VERSION 5.7 ;
  NOWIREEXTENSIONATPIN ON ;
  DIVIDERCHAR "/" ;
  BUSBITCHARS "[]" ;
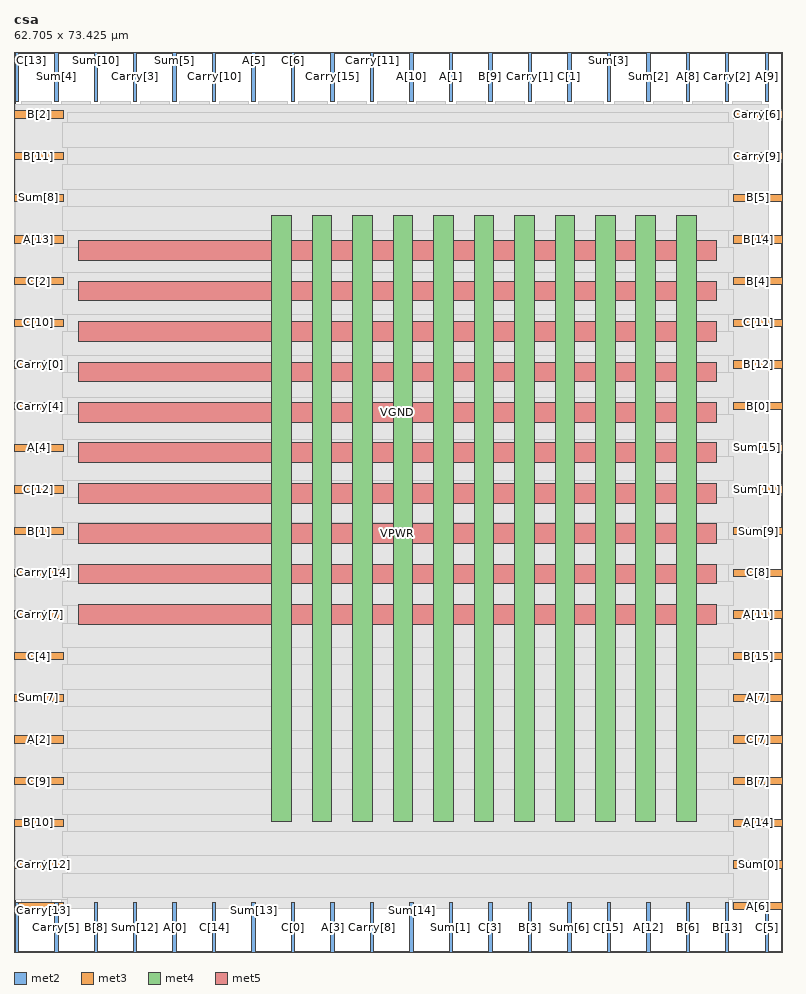
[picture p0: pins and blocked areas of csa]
MACRO csa
  CLASS BLOCK ;
  FOREIGN csa ;
  ORIGIN 0.000 0.000 ;
  SIZE 62.705 BY 73.425 ;
  PIN A[0]
    DIRECTION INPUT ;
    USE SIGNAL ;
    ANTENNAGATEAREA 0.196500 ;
    PORT
      LAYER met2 ;
        RECT 12.970 0.000 13.250 4.000 ;
    END
  END A[0]
  PIN A[10]
    DIRECTION INPUT ;
    USE SIGNAL ;
    ANTENNAGATEAREA 0.196500 ;
    PORT
      LAYER met2 ;
        RECT 32.290 69.425 32.570 73.425 ;
    END
  END A[10]
  PIN A[11]
    DIRECTION INPUT ;
    USE SIGNAL ;
    ANTENNAGATEAREA 0.196500 ;
    PORT
      LAYER met3 ;
        RECT 58.705 27.240 62.705 27.840 ;
    END
  END A[11]
  PIN A[12]
    DIRECTION INPUT ;
    USE SIGNAL ;
    ANTENNAGATEAREA 0.126000 ;
    PORT
      LAYER met2 ;
        RECT 51.610 0.000 51.890 4.000 ;
    END
  END A[12]
  PIN A[13]
    DIRECTION INPUT ;
    USE SIGNAL ;
    ANTENNAGATEAREA 0.196500 ;
    PORT
      LAYER met3 ;
        RECT 0.000 57.840 4.000 58.440 ;
    END
  END A[13]
  PIN A[14]
    DIRECTION INPUT ;
    USE SIGNAL ;
    ANTENNAGATEAREA 0.196500 ;
    PORT
      LAYER met3 ;
        RECT 58.705 10.240 62.705 10.840 ;
    END
  END A[14]
  PIN A[15]
    DIRECTION INPUT ;
    USE SIGNAL ;
    ANTENNAGATEAREA 0.126000 ;
    PORT
      LAYER met3 ;
        RECT 0.000 3.440 4.000 4.040 ;
    END
  END A[15]
  PIN A[1]
    DIRECTION INPUT ;
    USE SIGNAL ;
    ANTENNAGATEAREA 0.196500 ;
    PORT
      LAYER met2 ;
        RECT 35.510 69.425 35.790 73.425 ;
    END
  END A[1]
  PIN A[2]
    DIRECTION INPUT ;
    USE SIGNAL ;
    ANTENNAGATEAREA 0.126000 ;
    PORT
      LAYER met3 ;
        RECT 0.000 17.040 4.000 17.640 ;
    END
  END A[2]
  PIN A[3]
    DIRECTION INPUT ;
    USE SIGNAL ;
    ANTENNAGATEAREA 0.196500 ;
    PORT
      LAYER met2 ;
        RECT 25.850 0.000 26.130 4.000 ;
    END
  END A[3]
  PIN A[4]
    DIRECTION INPUT ;
    USE SIGNAL ;
    ANTENNAGATEAREA 0.196500 ;
    PORT
      LAYER met3 ;
        RECT 0.000 40.840 4.000 41.440 ;
    END
  END A[4]
  PIN A[5]
    DIRECTION INPUT ;
    USE SIGNAL ;
    ANTENNAGATEAREA 0.196500 ;
    PORT
      LAYER met2 ;
        RECT 19.410 69.425 19.690 73.425 ;
    END
  END A[5]
  PIN A[6]
    DIRECTION INPUT ;
    USE SIGNAL ;
    ANTENNAGATEAREA 0.196500 ;
    PORT
      LAYER met3 ;
        RECT 58.705 3.440 62.705 4.040 ;
    END
  END A[6]
  PIN A[7]
    DIRECTION INPUT ;
    USE SIGNAL ;
    ANTENNAGATEAREA 0.196500 ;
    PORT
      LAYER met3 ;
        RECT 58.705 20.440 62.705 21.040 ;
    END
  END A[7]
  PIN A[8]
    DIRECTION INPUT ;
    USE SIGNAL ;
    ANTENNAGATEAREA 0.196500 ;
    PORT
      LAYER met2 ;
        RECT 54.830 69.425 55.110 73.425 ;
    END
  END A[8]
  PIN A[9]
    DIRECTION INPUT ;
    USE SIGNAL ;
    ANTENNAGATEAREA 0.196500 ;
    PORT
      LAYER met2 ;
        RECT 61.270 69.425 61.550 73.425 ;
    END
  END A[9]
  PIN B[0]
    DIRECTION INPUT ;
    USE SIGNAL ;
    ANTENNAGATEAREA 0.126000 ;
    PORT
      LAYER met3 ;
        RECT 58.705 44.240 62.705 44.840 ;
    END
  END B[0]
  PIN B[10]
    DIRECTION INPUT ;
    USE SIGNAL ;
    ANTENNAGATEAREA 0.196500 ;
    PORT
      LAYER met3 ;
        RECT 0.000 10.240 4.000 10.840 ;
    END
  END B[10]
  PIN B[11]
    DIRECTION INPUT ;
    USE SIGNAL ;
    ANTENNAGATEAREA 0.196500 ;
    PORT
      LAYER met3 ;
        RECT 0.000 64.640 4.000 65.240 ;
    END
  END B[11]
  PIN B[12]
    DIRECTION INPUT ;
    USE SIGNAL ;
    ANTENNAGATEAREA 0.126000 ;
    PORT
      LAYER met3 ;
        RECT 58.705 47.640 62.705 48.240 ;
    END
  END B[12]
  PIN B[13]
    DIRECTION INPUT ;
    USE SIGNAL ;
    ANTENNAGATEAREA 0.196500 ;
    PORT
      LAYER met2 ;
        RECT 58.050 0.000 58.330 4.000 ;
    END
  END B[13]
  PIN B[14]
    DIRECTION INPUT ;
    USE SIGNAL ;
    ANTENNAGATEAREA 0.126000 ;
    PORT
      LAYER met3 ;
        RECT 58.705 57.840 62.705 58.440 ;
    END
  END B[14]
  PIN B[15]
    DIRECTION INPUT ;
    USE SIGNAL ;
    ANTENNAGATEAREA 0.196500 ;
    PORT
      LAYER met3 ;
        RECT 58.705 23.840 62.705 24.440 ;
    END
  END B[15]
  PIN B[1]
    DIRECTION INPUT ;
    USE SIGNAL ;
    ANTENNAGATEAREA 0.196500 ;
    PORT
      LAYER met3 ;
        RECT 0.000 34.040 4.000 34.640 ;
    END
  END B[1]
  PIN B[2]
    DIRECTION INPUT ;
    USE SIGNAL ;
    ANTENNAGATEAREA 0.196500 ;
    PORT
      LAYER met3 ;
        RECT 0.000 68.040 4.000 68.640 ;
    END
  END B[2]
  PIN B[3]
    DIRECTION INPUT ;
    USE SIGNAL ;
    ANTENNAGATEAREA 0.196500 ;
    PORT
      LAYER met2 ;
        RECT 41.950 0.000 42.230 4.000 ;
    END
  END B[3]
  PIN B[4]
    DIRECTION INPUT ;
    USE SIGNAL ;
    ANTENNAGATEAREA 0.196500 ;
    PORT
      LAYER met3 ;
        RECT 58.705 54.440 62.705 55.040 ;
    END
  END B[4]
  PIN B[5]
    DIRECTION INPUT ;
    USE SIGNAL ;
    ANTENNAGATEAREA 0.196500 ;
    PORT
      LAYER met3 ;
        RECT 58.705 61.240 62.705 61.840 ;
    END
  END B[5]
  PIN B[6]
    DIRECTION INPUT ;
    USE SIGNAL ;
    ANTENNAGATEAREA 0.196500 ;
    PORT
      LAYER met2 ;
        RECT 54.830 0.000 55.110 4.000 ;
    END
  END B[6]
  PIN B[7]
    DIRECTION INPUT ;
    USE SIGNAL ;
    ANTENNAGATEAREA 0.196500 ;
    PORT
      LAYER met3 ;
        RECT 58.705 13.640 62.705 14.240 ;
    END
  END B[7]
  PIN B[8]
    DIRECTION INPUT ;
    USE SIGNAL ;
    ANTENNAGATEAREA 0.196500 ;
    PORT
      LAYER met2 ;
        RECT 6.530 0.000 6.810 4.000 ;
    END
  END B[8]
  PIN B[9]
    DIRECTION INPUT ;
    USE SIGNAL ;
    ANTENNAGATEAREA 0.196500 ;
    PORT
      LAYER met2 ;
        RECT 38.730 69.425 39.010 73.425 ;
    END
  END B[9]
  PIN C[0]
    DIRECTION INPUT ;
    USE SIGNAL ;
    ANTENNAGATEAREA 0.196500 ;
    PORT
      LAYER met2 ;
        RECT 22.630 0.000 22.910 4.000 ;
    END
  END C[0]
  PIN C[10]
    DIRECTION INPUT ;
    USE SIGNAL ;
    ANTENNAGATEAREA 0.196500 ;
    PORT
      LAYER met3 ;
        RECT 0.000 51.040 4.000 51.640 ;
    END
  END C[10]
  PIN C[11]
    DIRECTION INPUT ;
    USE SIGNAL ;
    ANTENNAGATEAREA 0.196500 ;
    PORT
      LAYER met3 ;
        RECT 58.705 51.040 62.705 51.640 ;
    END
  END C[11]
  PIN C[12]
    DIRECTION INPUT ;
    USE SIGNAL ;
    ANTENNAGATEAREA 0.196500 ;
    PORT
      LAYER met3 ;
        RECT 0.000 37.440 4.000 38.040 ;
    END
  END C[12]
  PIN C[13]
    DIRECTION INPUT ;
    USE SIGNAL ;
    ANTENNAGATEAREA 0.196500 ;
    PORT
      LAYER met2 ;
        RECT 0.090 69.425 0.370 73.425 ;
    END
  END C[13]
  PIN C[14]
    DIRECTION INPUT ;
    USE SIGNAL ;
    ANTENNAGATEAREA 0.196500 ;
    PORT
      LAYER met2 ;
        RECT 16.190 0.000 16.470 4.000 ;
    END
  END C[14]
  PIN C[15]
    DIRECTION INPUT ;
    USE SIGNAL ;
    ANTENNAGATEAREA 0.196500 ;
    PORT
      LAYER met2 ;
        RECT 48.390 0.000 48.670 4.000 ;
    END
  END C[15]
  PIN C[1]
    DIRECTION INPUT ;
    USE SIGNAL ;
    ANTENNAGATEAREA 0.196500 ;
    PORT
      LAYER met2 ;
        RECT 45.170 69.425 45.450 73.425 ;
    END
  END C[1]
  PIN C[2]
    DIRECTION INPUT ;
    USE SIGNAL ;
    ANTENNAGATEAREA 0.196500 ;
    PORT
      LAYER met3 ;
        RECT 0.000 54.440 4.000 55.040 ;
    END
  END C[2]
  PIN C[3]
    DIRECTION INPUT ;
    USE SIGNAL ;
    ANTENNAGATEAREA 0.196500 ;
    PORT
      LAYER met2 ;
        RECT 38.730 0.000 39.010 4.000 ;
    END
  END C[3]
  PIN C[4]
    DIRECTION INPUT ;
    USE SIGNAL ;
    ANTENNAGATEAREA 0.196500 ;
    PORT
      LAYER met3 ;
        RECT 0.000 23.840 4.000 24.440 ;
    END
  END C[4]
  PIN C[5]
    DIRECTION INPUT ;
    USE SIGNAL ;
    ANTENNAGATEAREA 0.196500 ;
    PORT
      LAYER met2 ;
        RECT 61.270 0.000 61.550 4.000 ;
    END
  END C[5]
  PIN C[6]
    DIRECTION INPUT ;
    USE SIGNAL ;
    ANTENNAGATEAREA 0.196500 ;
    PORT
      LAYER met2 ;
        RECT 22.630 69.425 22.910 73.425 ;
    END
  END C[6]
  PIN C[7]
    DIRECTION INPUT ;
    USE SIGNAL ;
    ANTENNAGATEAREA 0.196500 ;
    PORT
      LAYER met3 ;
        RECT 58.705 17.040 62.705 17.640 ;
    END
  END C[7]
  PIN C[8]
    DIRECTION INPUT ;
    USE SIGNAL ;
    ANTENNAGATEAREA 0.196500 ;
    PORT
      LAYER met3 ;
        RECT 58.705 30.640 62.705 31.240 ;
    END
  END C[8]
  PIN C[9]
    DIRECTION INPUT ;
    USE SIGNAL ;
    ANTENNAGATEAREA 0.196500 ;
    PORT
      LAYER met3 ;
        RECT 0.000 13.640 4.000 14.240 ;
    END
  END C[9]
  PIN Carry[0]
    DIRECTION OUTPUT TRISTATE ;
    USE SIGNAL ;
    ANTENNADIFFAREA 0.795200 ;
    PORT
      LAYER met3 ;
        RECT 0.000 47.640 4.000 48.240 ;
    END
  END Carry[0]
  PIN Carry[10]
    DIRECTION OUTPUT TRISTATE ;
    USE SIGNAL ;
    ANTENNADIFFAREA 0.795200 ;
    PORT
      LAYER met2 ;
        RECT 16.190 69.425 16.470 73.425 ;
    END
  END Carry[10]
  PIN Carry[11]
    DIRECTION OUTPUT TRISTATE ;
    USE SIGNAL ;
    ANTENNADIFFAREA 0.795200 ;
    PORT
      LAYER met2 ;
        RECT 29.070 69.425 29.350 73.425 ;
    END
  END Carry[11]
  PIN Carry[12]
    DIRECTION OUTPUT TRISTATE ;
    USE SIGNAL ;
    ANTENNADIFFAREA 0.795200 ;
    PORT
      LAYER met3 ;
        RECT 0.000 6.840 4.000 7.440 ;
    END
  END Carry[12]
  PIN Carry[13]
    DIRECTION OUTPUT TRISTATE ;
    USE SIGNAL ;
    ANTENNADIFFAREA 0.795200 ;
    PORT
      LAYER met2 ;
        RECT 0.090 0.000 0.370 4.000 ;
    END
  END Carry[13]
  PIN Carry[14]
    DIRECTION OUTPUT TRISTATE ;
    USE SIGNAL ;
    ANTENNADIFFAREA 0.795200 ;
    PORT
      LAYER met3 ;
        RECT 0.000 30.640 4.000 31.240 ;
    END
  END Carry[14]
  PIN Carry[15]
    DIRECTION OUTPUT TRISTATE ;
    USE SIGNAL ;
    ANTENNADIFFAREA 0.795200 ;
    PORT
      LAYER met2 ;
        RECT 25.850 69.425 26.130 73.425 ;
    END
  END Carry[15]
  PIN Carry[1]
    DIRECTION OUTPUT TRISTATE ;
    USE SIGNAL ;
    ANTENNADIFFAREA 0.795200 ;
    PORT
      LAYER met2 ;
        RECT 41.950 69.425 42.230 73.425 ;
    END
  END Carry[1]
  PIN Carry[2]
    DIRECTION OUTPUT TRISTATE ;
    USE SIGNAL ;
    ANTENNADIFFAREA 0.795200 ;
    PORT
      LAYER met2 ;
        RECT 58.050 69.425 58.330 73.425 ;
    END
  END Carry[2]
  PIN Carry[3]
    DIRECTION OUTPUT TRISTATE ;
    USE SIGNAL ;
    ANTENNADIFFAREA 0.795200 ;
    PORT
      LAYER met2 ;
        RECT 9.750 69.425 10.030 73.425 ;
    END
  END Carry[3]
  PIN Carry[4]
    DIRECTION OUTPUT TRISTATE ;
    USE SIGNAL ;
    ANTENNADIFFAREA 0.795200 ;
    PORT
      LAYER met3 ;
        RECT 0.000 44.240 4.000 44.840 ;
    END
  END Carry[4]
  PIN Carry[5]
    DIRECTION OUTPUT TRISTATE ;
    USE SIGNAL ;
    ANTENNADIFFAREA 0.795200 ;
    PORT
      LAYER met2 ;
        RECT 3.310 0.000 3.590 4.000 ;
    END
  END Carry[5]
  PIN Carry[6]
    DIRECTION OUTPUT TRISTATE ;
    USE SIGNAL ;
    ANTENNADIFFAREA 0.795200 ;
    PORT
      LAYER met3 ;
        RECT 58.705 68.040 62.705 68.640 ;
    END
  END Carry[6]
  PIN Carry[7]
    DIRECTION OUTPUT TRISTATE ;
    USE SIGNAL ;
    ANTENNADIFFAREA 0.795200 ;
    PORT
      LAYER met3 ;
        RECT 0.000 27.240 4.000 27.840 ;
    END
  END Carry[7]
  PIN Carry[8]
    DIRECTION OUTPUT TRISTATE ;
    USE SIGNAL ;
    ANTENNADIFFAREA 0.795200 ;
    PORT
      LAYER met2 ;
        RECT 29.070 0.000 29.350 4.000 ;
    END
  END Carry[8]
  PIN Carry[9]
    DIRECTION OUTPUT TRISTATE ;
    USE SIGNAL ;
    ANTENNADIFFAREA 0.795200 ;
    PORT
      LAYER met3 ;
        RECT 58.705 64.640 62.705 65.240 ;
    END
  END Carry[9]
  PIN Sum[0]
    DIRECTION OUTPUT TRISTATE ;
    USE SIGNAL ;
    ANTENNADIFFAREA 0.795200 ;
    PORT
      LAYER met3 ;
        RECT 58.705 6.840 62.705 7.440 ;
    END
  END Sum[0]
  PIN Sum[10]
    DIRECTION OUTPUT TRISTATE ;
    USE SIGNAL ;
    ANTENNADIFFAREA 0.795200 ;
    PORT
      LAYER met2 ;
        RECT 6.530 69.425 6.810 73.425 ;
    END
  END Sum[10]
  PIN Sum[11]
    DIRECTION OUTPUT TRISTATE ;
    USE SIGNAL ;
    ANTENNADIFFAREA 0.795200 ;
    PORT
      LAYER met3 ;
        RECT 58.705 37.440 62.705 38.040 ;
    END
  END Sum[11]
  PIN Sum[12]
    DIRECTION OUTPUT TRISTATE ;
    USE SIGNAL ;
    ANTENNADIFFAREA 0.795200 ;
    PORT
      LAYER met2 ;
        RECT 9.750 0.000 10.030 4.000 ;
    END
  END Sum[12]
  PIN Sum[13]
    DIRECTION OUTPUT TRISTATE ;
    USE SIGNAL ;
    ANTENNADIFFAREA 0.795200 ;
    PORT
      LAYER met2 ;
        RECT 19.410 0.000 19.690 4.000 ;
    END
  END Sum[13]
  PIN Sum[14]
    DIRECTION OUTPUT TRISTATE ;
    USE SIGNAL ;
    ANTENNADIFFAREA 0.795200 ;
    PORT
      LAYER met2 ;
        RECT 32.290 0.000 32.570 4.000 ;
    END
  END Sum[14]
  PIN Sum[15]
    DIRECTION OUTPUT TRISTATE ;
    USE SIGNAL ;
    ANTENNADIFFAREA 0.795200 ;
    PORT
      LAYER met3 ;
        RECT 58.705 40.840 62.705 41.440 ;
    END
  END Sum[15]
  PIN Sum[1]
    DIRECTION OUTPUT TRISTATE ;
    USE SIGNAL ;
    ANTENNADIFFAREA 0.795200 ;
    PORT
      LAYER met2 ;
        RECT 35.510 0.000 35.790 4.000 ;
    END
  END Sum[1]
  PIN Sum[2]
    DIRECTION OUTPUT TRISTATE ;
    USE SIGNAL ;
    ANTENNADIFFAREA 0.795200 ;
    PORT
      LAYER met2 ;
        RECT 51.610 69.425 51.890 73.425 ;
    END
  END Sum[2]
  PIN Sum[3]
    DIRECTION OUTPUT TRISTATE ;
    USE SIGNAL ;
    ANTENNADIFFAREA 0.795200 ;
    PORT
      LAYER met2 ;
        RECT 48.390 69.425 48.670 73.425 ;
    END
  END Sum[3]
  PIN Sum[4]
    DIRECTION OUTPUT TRISTATE ;
    USE SIGNAL ;
    ANTENNADIFFAREA 0.795200 ;
    PORT
      LAYER met2 ;
        RECT 3.310 69.425 3.590 73.425 ;
    END
  END Sum[4]
  PIN Sum[5]
    DIRECTION OUTPUT TRISTATE ;
    USE SIGNAL ;
    ANTENNADIFFAREA 0.795200 ;
    PORT
      LAYER met2 ;
        RECT 12.970 69.425 13.250 73.425 ;
    END
  END Sum[5]
  PIN Sum[6]
    DIRECTION OUTPUT TRISTATE ;
    USE SIGNAL ;
    ANTENNADIFFAREA 0.795200 ;
    PORT
      LAYER met2 ;
        RECT 45.170 0.000 45.450 4.000 ;
    END
  END Sum[6]
  PIN Sum[7]
    DIRECTION OUTPUT TRISTATE ;
    USE SIGNAL ;
    ANTENNADIFFAREA 0.795200 ;
    PORT
      LAYER met3 ;
        RECT 0.000 20.440 4.000 21.040 ;
    END
  END Sum[7]
  PIN Sum[8]
    DIRECTION OUTPUT TRISTATE ;
    USE SIGNAL ;
    ANTENNADIFFAREA 0.795200 ;
    PORT
      LAYER met3 ;
        RECT 0.000 61.240 4.000 61.840 ;
    END
  END Sum[8]
  PIN Sum[9]
    DIRECTION OUTPUT TRISTATE ;
    USE SIGNAL ;
    ANTENNADIFFAREA 0.795200 ;
    PORT
      LAYER met3 ;
        RECT 58.705 34.040 62.705 34.640 ;
    END
  END Sum[9]
  PIN VGND
    DIRECTION INOUT ;
    USE GROUND ;
    PORT
      LAYER met4 ;
        RECT 24.340 10.640 25.940 60.080 ;
    END
    PORT
      LAYER met4 ;
        RECT 30.940 10.640 32.540 60.080 ;
    END
    PORT
      LAYER met4 ;
        RECT 37.540 10.640 39.140 60.080 ;
    END
    PORT
      LAYER met4 ;
        RECT 44.140 10.640 45.740 60.080 ;
    END
    PORT
      LAYER met4 ;
        RECT 50.740 10.640 52.340 60.080 ;
    END
    PORT
      LAYER met5 ;
        RECT 5.280 30.030 57.280 31.630 ;
    END
    PORT
      LAYER met5 ;
        RECT 5.280 36.630 57.280 38.230 ;
    END
    PORT
      LAYER met5 ;
        RECT 5.280 43.230 57.280 44.830 ;
    END
    PORT
      LAYER met5 ;
        RECT 5.280 49.830 57.280 51.430 ;
    END
    PORT
      LAYER met5 ;
        RECT 5.280 56.430 57.280 58.030 ;
    END
  END VGND
  PIN VPWR
    DIRECTION INOUT ;
    USE POWER ;
    PORT
      LAYER met4 ;
        RECT 21.040 10.640 22.640 60.080 ;
    END
    PORT
      LAYER met4 ;
        RECT 27.640 10.640 29.240 60.080 ;
    END
    PORT
      LAYER met4 ;
        RECT 34.240 10.640 35.840 60.080 ;
    END
    PORT
      LAYER met4 ;
        RECT 40.840 10.640 42.440 60.080 ;
    END
    PORT
      LAYER met4 ;
        RECT 47.440 10.640 49.040 60.080 ;
    END
    PORT
      LAYER met4 ;
        RECT 54.040 10.640 55.640 60.080 ;
    END
    PORT
      LAYER met5 ;
        RECT 5.280 26.730 57.280 28.330 ;
    END
    PORT
      LAYER met5 ;
        RECT 5.280 33.330 57.280 34.930 ;
    END
    PORT
      LAYER met5 ;
        RECT 5.280 39.930 57.280 41.530 ;
    END
    PORT
      LAYER met5 ;
        RECT 5.280 46.530 57.280 48.130 ;
    END
    PORT
      LAYER met5 ;
        RECT 5.280 53.130 57.280 54.730 ;
    END
  END VPWR
  OBS
      LAYER li1 ;
        RECT 5.520 10.795 57.040 59.925 ;
      LAYER met1 ;
        RECT 0.070 10.240 61.570 61.160 ;
      LAYER met2 ;
        RECT 0.650 69.145 3.030 69.425 ;
        RECT 3.870 69.145 6.250 69.425 ;
        RECT 7.090 69.145 9.470 69.425 ;
        RECT 10.310 69.145 12.690 69.425 ;
        RECT 13.530 69.145 15.910 69.425 ;
        RECT 16.750 69.145 19.130 69.425 ;
        RECT 19.970 69.145 22.350 69.425 ;
        RECT 23.190 69.145 25.570 69.425 ;
        RECT 26.410 69.145 28.790 69.425 ;
        RECT 29.630 69.145 32.010 69.425 ;
        RECT 32.850 69.145 35.230 69.425 ;
        RECT 36.070 69.145 38.450 69.425 ;
        RECT 39.290 69.145 41.670 69.425 ;
        RECT 42.510 69.145 44.890 69.425 ;
        RECT 45.730 69.145 48.110 69.425 ;
        RECT 48.950 69.145 51.330 69.425 ;
        RECT 52.170 69.145 54.550 69.425 ;
        RECT 55.390 69.145 57.770 69.425 ;
        RECT 58.610 69.145 60.990 69.425 ;
        RECT 0.100 4.280 61.540 69.145 ;
        RECT 0.650 3.555 3.030 4.280 ;
        RECT 3.870 3.555 6.250 4.280 ;
        RECT 7.090 3.555 9.470 4.280 ;
        RECT 10.310 3.555 12.690 4.280 ;
        RECT 13.530 3.555 15.910 4.280 ;
        RECT 16.750 3.555 19.130 4.280 ;
        RECT 19.970 3.555 22.350 4.280 ;
        RECT 23.190 3.555 25.570 4.280 ;
        RECT 26.410 3.555 28.790 4.280 ;
        RECT 29.630 3.555 32.010 4.280 ;
        RECT 32.850 3.555 35.230 4.280 ;
        RECT 36.070 3.555 38.450 4.280 ;
        RECT 39.290 3.555 41.670 4.280 ;
        RECT 42.510 3.555 44.890 4.280 ;
        RECT 45.730 3.555 48.110 4.280 ;
        RECT 48.950 3.555 51.330 4.280 ;
        RECT 52.170 3.555 54.550 4.280 ;
        RECT 55.390 3.555 57.770 4.280 ;
        RECT 58.610 3.555 60.990 4.280 ;
      LAYER met3 ;
        RECT 4.400 67.640 58.305 68.505 ;
        RECT 3.990 65.640 58.705 67.640 ;
        RECT 4.400 64.240 58.305 65.640 ;
        RECT 3.990 62.240 58.705 64.240 ;
        RECT 4.400 60.840 58.305 62.240 ;
        RECT 3.990 58.840 58.705 60.840 ;
        RECT 4.400 57.440 58.305 58.840 ;
        RECT 3.990 55.440 58.705 57.440 ;
        RECT 4.400 54.040 58.305 55.440 ;
        RECT 3.990 52.040 58.705 54.040 ;
        RECT 4.400 50.640 58.305 52.040 ;
        RECT 3.990 48.640 58.705 50.640 ;
        RECT 4.400 47.240 58.305 48.640 ;
        RECT 3.990 45.240 58.705 47.240 ;
        RECT 4.400 43.840 58.305 45.240 ;
        RECT 3.990 41.840 58.705 43.840 ;
        RECT 4.400 40.440 58.305 41.840 ;
        RECT 3.990 38.440 58.705 40.440 ;
        RECT 4.400 37.040 58.305 38.440 ;
        RECT 3.990 35.040 58.705 37.040 ;
        RECT 4.400 33.640 58.305 35.040 ;
        RECT 3.990 31.640 58.705 33.640 ;
        RECT 4.400 30.240 58.305 31.640 ;
        RECT 3.990 28.240 58.705 30.240 ;
        RECT 4.400 26.840 58.305 28.240 ;
        RECT 3.990 24.840 58.705 26.840 ;
        RECT 4.400 23.440 58.305 24.840 ;
        RECT 3.990 21.440 58.705 23.440 ;
        RECT 4.400 20.040 58.305 21.440 ;
        RECT 3.990 18.040 58.705 20.040 ;
        RECT 4.400 16.640 58.305 18.040 ;
        RECT 3.990 14.640 58.705 16.640 ;
        RECT 4.400 13.240 58.305 14.640 ;
        RECT 3.990 11.240 58.705 13.240 ;
        RECT 4.400 9.840 58.305 11.240 ;
        RECT 3.990 7.840 58.705 9.840 ;
        RECT 4.400 6.440 58.305 7.840 ;
        RECT 3.990 4.440 58.705 6.440 ;
        RECT 4.400 3.575 58.305 4.440 ;
  END
END csa
END LIBRARY

